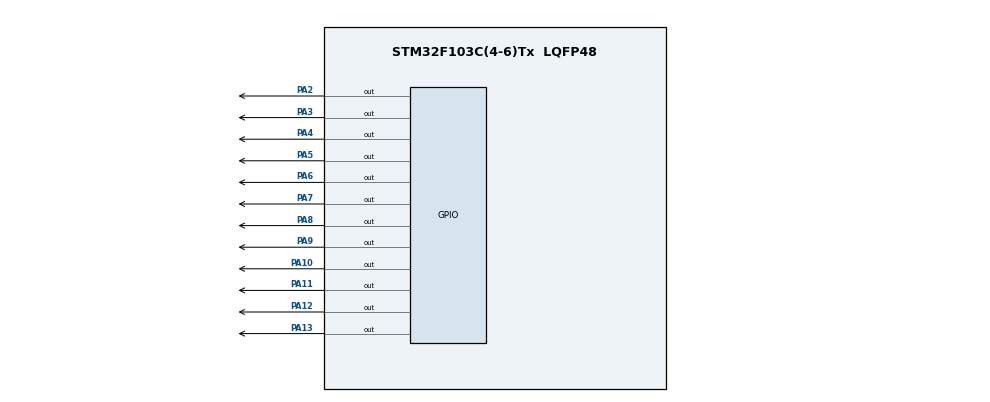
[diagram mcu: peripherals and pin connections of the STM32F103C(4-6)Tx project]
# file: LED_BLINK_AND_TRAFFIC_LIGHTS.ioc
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Mcu.Family=STM32F1
Mcu.Name=STM32F103C(4-6)Tx
Mcu.Package=LQFP48
NVIC.PriorityGroup=NVIC_PRIORITYGROUP_4
PA10.Signal=GPIO_Output
PA11.Signal=GPIO_Output
PA12.Signal=GPIO_Output
PA13.Signal=GPIO_Output
PA2.Signal=GPIO_Output
PA3.Signal=GPIO_Output
PA4.Signal=GPIO_Output
PA5.Signal=GPIO_Output
PA6.Signal=GPIO_Output
PA7.Signal=GPIO_Output
PA8.Signal=GPIO_Output
PA9.Signal=GPIO_Output
PD0-OSC_IN.Mode=HSE-External-Oscillator
PD0-OSC_IN.Signal=RCC_OSC_IN
PD1-OSC_OUT.Mode=HSE-External-Oscillator
PD1-OSC_OUT.Signal=RCC_OSC_OUT
ProjectManager.HeapSize=0x200
ProjectManager.StackSize=0x400
ProjectManager.TargetToolchain=STM32CubeIDE
RCC.APB1Freq_Value=8000000
RCC.APB2Freq_Value=8000000
VP_SYS_VS_ND.Mode=No_Debug
board=custom

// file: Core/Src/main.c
/* USER CODE BEGIN Header */
/**
  ******************************************************************************
  * @file           : main.c
  * @brief          : Main program body
  ******************************************************************************
  * @attention
  *
  * <h2><center>&copy; Copyright (c) 2021 STMicroelectronics.
  * All rights reserved.</center></h2>
  *
  * This software component is licensed by ST under BSD 3-Clause license,
  * the "License"; You may not use this file except in compliance with the
  * License. You may obtain a copy of the License at:
  *                        opensource.org/licenses/BSD-3-Clause
  *
  ******************************************************************************
  */
/* USER CODE END Header */
#include "main.h"

/* USER CODE BEGIN Includes */
#include "led_7seg_anode.h"
/* USER CODE END Includes */

/* USER CODE BEGIN PD */
// Gate of LED
#define RED1 GPIO_PIN_1
#define YELLOW1 GPIO_PIN_2
#define GREEN1 GPIO_PIN_3
#define RED2 GPIO_PIN_4
#define YELLOW2 GPIO_PIN_5
#define GREEN2 GPIO_PIN_6
// define sign
#define ON RESET
#define OFF SET
//Counter
#define R_COUNTER 5
#define Y_COUNTER 2
#define G_COUNTER 3
#define LED_DELAY 500

/* USER CODE END PD */

/* USER CODE BEGIN PV */

 uint16_t RedLED[NUMS_7SEGS] = {RED1,RED2};
 uint16_t YellowLED[NUMS_7SEGS] = {YELLOW1,YELLOW2};
 uint16_t GreenLED[NUMS_7SEGS] = {GREEN1,GREEN2};
 uint16_t *typeLED[3] = {RedLED,YellowLED,GreenLED};
static uint8_t counterBuffer[3] = {R_COUNTER,Y_COUNTER,G_COUNTER};
/* USER CODE END PV */

void SystemClock_Config(void);
static void MX_GPIO_Init(void);

/* USER CODE BEGIN 0 */
void initLED(void){
	HAL_GPIO_WritePin(GPIOA, RED1, OFF);
	HAL_GPIO_WritePin(GPIOA, YELLOW1, OFF);
	HAL_GPIO_WritePin(GPIOA, GREEN1, OFF);
	HAL_GPIO_WritePin(GPIOA, RED2, OFF);
	HAL_GPIO_WritePin(GPIOA, YELLOW2, OFF);
	HAL_GPIO_WritePin(GPIOA, GREEN2, OFF);
}

void trafficLIGHTDisplay(int idx,int val){
	updatesevenSegmentLEDBuffer(val,idx);
	sevenSegementLEDDriver(idx);
}
void trafficLIGHTStart(int led,int idx){
	  HAL_GPIO_WritePin(GPIOA, typeLED[led][idx], ON);
	  HAL_GPIO_WritePin(GPIOA, typeLED[led][idx], ON);
}
void trafficLIGHTChangeColor(int led,int idx){
	HAL_GPIO_WritePin(GPIOA, typeLED[(led)%3][idx], OFF);
	HAL_GPIO_WritePin(GPIOA, typeLED[(led+1)%3][idx], ON);
}
/* USER CODE END 0 */

int main(void)
{

  /* MCU Configuration--------------------------------------------------------*/

  /* Reset of all peripherals, Initializes the Flash interface and the Systick. */
  HAL_Init();

  /* Configure the system clock */
  SystemClock_Config();

  /* Initialize all configured peripherals */
  MX_GPIO_Init();

  /* Infinite loop */
  /* USER CODE BEGIN WHILE */
  enum {RED,YELLOW,GREEN};
  int color1 = RED;
  int color2 = YELLOW;
  int limit1 = counterBuffer[color1];
  int limit2 = counterBuffer[color2];

  sevenSegmentLEDInit();
  initLED();
  trafficLIGHTStart(color1, 0);
  trafficLIGHTStart(color2, 1);
  while (1)
  {

	 /* USER CODE END WHILE */

    /* USER CODE BEGIN 3 */
	  trafficLIGHTDisplay(0,limit1);
	  trafficLIGHTDisplay(1,limit2);
	  HAL_Delay(LED_DELAY);
	  --limit1;
	  --limit2;
	  if(limit1 == -1){
		  trafficLIGHTChangeColor(color1,0);
		  ++color1;
		  limit1 = counterBuffer[color1 %3];

	  }
	  if(limit2 == -1){
		  trafficLIGHTChangeColor(color2,1);
		  ++color2;
		  limit2 = counterBuffer[color2%3];

	  }
  }
  /* USER CODE END 3 */
}

void SystemClock_Config(void)
{
  RCC_OscInitTypeDef RCC_OscInitStruct = {0};
  RCC_ClkInitTypeDef RCC_ClkInitStruct = {0};

  /** Initializes the RCC Oscillators according to the specified parameters
  * in the RCC_OscInitTypeDef structure.
  */
  RCC_OscInitStruct.OscillatorType = RCC_OSCILLATORTYPE_HSI;
  RCC_OscInitStruct.HSIState = RCC_HSI_ON;
  RCC_OscInitStruct.HSICalibrationValue = RCC_HSICALIBRATION_DEFAULT;
  RCC_OscInitStruct.PLL.PLLState = RCC_PLL_NONE;
  if (HAL_RCC_OscConfig(&RCC_OscInitStruct) != HAL_OK)
  {
    Error_Handler();
  }
  /** Initializes the CPU, AHB and APB buses clocks
  */
  RCC_ClkInitStruct.ClockType = RCC_CLOCKTYPE_HCLK|RCC_CLOCKTYPE_SYSCLK
                              |RCC_CLOCKTYPE_PCLK1|RCC_CLOCKTYPE_PCLK2;
  RCC_ClkInitStruct.SYSCLKSource = RCC_SYSCLKSOURCE_HSI;
  RCC_ClkInitStruct.AHBCLKDivider = RCC_SYSCLK_DIV1;
  RCC_ClkInitStruct.APB1CLKDivider = RCC_HCLK_DIV1;
  RCC_ClkInitStruct.APB2CLKDivider = RCC_HCLK_DIV1;

  if (HAL_RCC_ClockConfig(&RCC_ClkInitStruct, FLASH_LATENCY_0) != HAL_OK)
  {
    Error_Handler();
  }
}

static void MX_GPIO_Init(void)
{
  GPIO_InitTypeDef GPIO_InitStruct = {0};

  /* GPIO Ports Clock Enable */
  __HAL_RCC_GPIOD_CLK_ENABLE();
  __HAL_RCC_GPIOA_CLK_ENABLE();
  __HAL_RCC_GPIOB_CLK_ENABLE();

  /*Configure GPIO pin Output Level */
  HAL_GPIO_WritePin(GPIOA, GPIO_PIN_1|GPIO_PIN_2|GPIO_PIN_3|GPIO_PIN_4
                          |GPIO_PIN_5|GPIO_PIN_6, GPIO_PIN_RESET);

  /*Configure GPIO pin Output Level */
  HAL_GPIO_WritePin(GPIOB, GPIO_PIN_0|GPIO_PIN_1|GPIO_PIN_2|GPIO_PIN_10
                          |GPIO_PIN_11|GPIO_PIN_12|GPIO_PIN_13|GPIO_PIN_3
                          |GPIO_PIN_4|GPIO_PIN_5|GPIO_PIN_6|GPIO_PIN_7
                          |GPIO_PIN_8|GPIO_PIN_9, GPIO_PIN_RESET);

  /*Configure GPIO pins : PA1 PA2 PA3 PA4
                           PA5 PA6 */
  GPIO_InitStruct.Pin = GPIO_PIN_1|GPIO_PIN_2|GPIO_PIN_3|GPIO_PIN_4
                          |GPIO_PIN_5|GPIO_PIN_6;
  GPIO_InitStruct.Mode = GPIO_MODE_OUTPUT_PP;
  GPIO_InitStruct.Pull = GPIO_NOPULL;
  GPIO_InitStruct.Speed = GPIO_SPEED_FREQ_LOW;
  HAL_GPIO_Init(GPIOA, &GPIO_InitStruct);

  /*Configure GPIO pins : PB0 PB1 PB2 PB10
                           PB11 PB12 PB13 PB3
                           PB4 PB5 PB6 PB7
                           PB8 PB9 */
  GPIO_InitStruct.Pin = GPIO_PIN_0|GPIO_PIN_1|GPIO_PIN_2|GPIO_PIN_10
                          |GPIO_PIN_11|GPIO_PIN_12|GPIO_PIN_13|GPIO_PIN_3
                          |GPIO_PIN_4|GPIO_PIN_5|GPIO_PIN_6|GPIO_PIN_7
                          |GPIO_PIN_8|GPIO_PIN_9;
  GPIO_InitStruct.Mode = GPIO_MODE_OUTPUT_PP;
  GPIO_InitStruct.Pull = GPIO_NOPULL;
  GPIO_InitStruct.Speed = GPIO_SPEED_FREQ_LOW;
  HAL_GPIO_Init(GPIOB, &GPIO_InitStruct);

}

void Error_Handler(void)
{
  __disable_irq();
  while (1)
  {
  }
}

/************************ (C) COPYRIGHT STMicroelectronics *****END OF FILE****/
